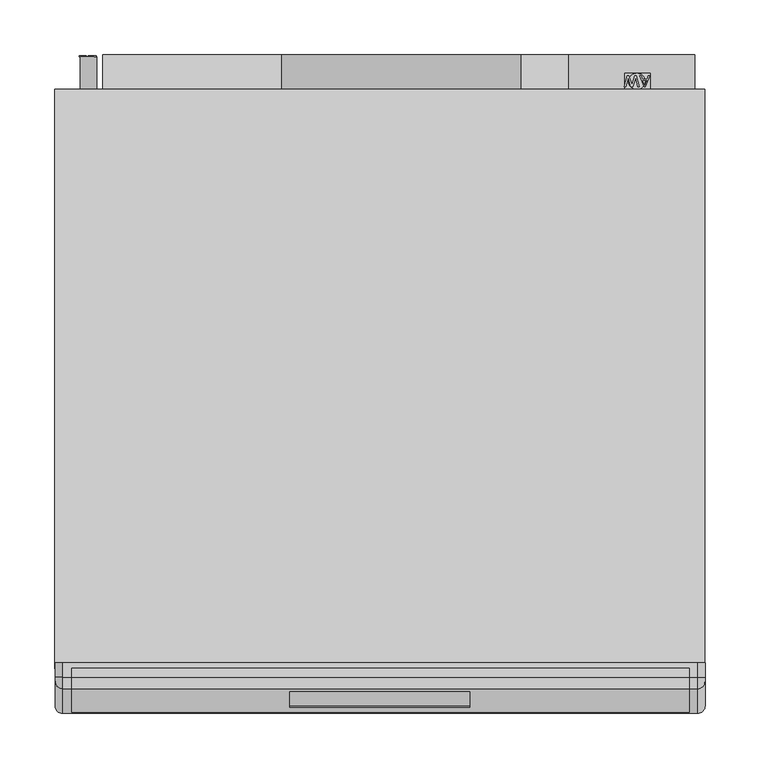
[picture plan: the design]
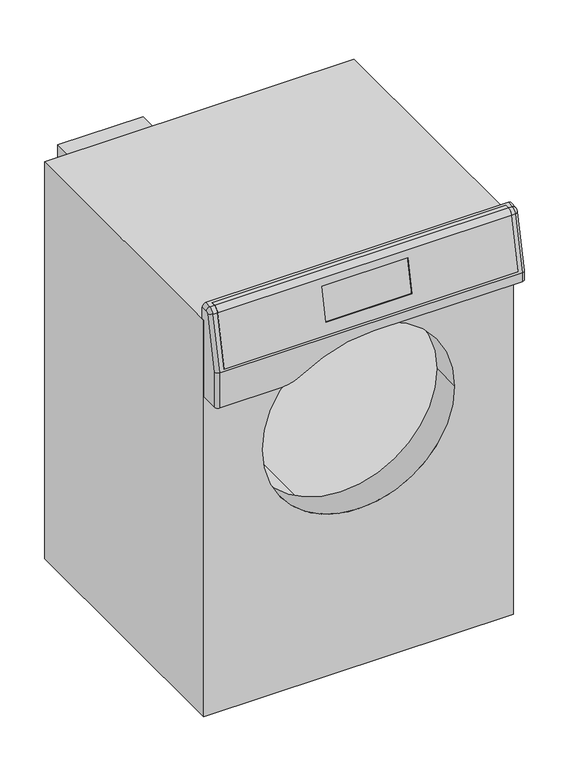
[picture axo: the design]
"""IFC4 building model written with IfcOpenShell, lengths in millimetres: proxy geometry."""

from ifc_helpers import new_model, si_unit, point, frame, frame_2d, origin, origin_with_axes, place, context, project, spatial, polyline, circle_curve, ellipse_curve, trimmed, segment, composite_curve, outline, extrude, source, transform, mapped, element, save
from ifc_brep_helpers import plane_surface, cylinder_surface, revolved_surface, advanced_brep


def specialty_equipment_5b1ebcfc(model_context):
    return source(origin(), model_context, "Body", "SolidModel", [
        advanced_brep(
        [(284.0, -576.5042463, 835.7290958), (284.0, -566.9845398, 843.6465521), (284.0, -558.5, 843.8687276), (284.0, -558.5, 844.8690704), (284.0, -567.0107168, 844.6462094), (284.0, -577.4823939, 835.9370075), (284.0, -599.1497738, 734.0), (284.0, -598.1274332, 734.0), (-282.0, -576.5042463, 835.7290958), (-282.0, -598.1274332, 734.0), (-282.0, -599.1497738, 734.0), (-282.0, -577.4823939, 835.9370075), (-282.0, -567.0107168, 844.6462094), (-282.0, -558.5, 844.8690704), (-282.0, -558.5, 843.8687276), (-282.0, -566.9845398, 843.6465521), (82.5, -580.4447963, 822.0), (82.5, -594.2609728, 757.0), (-82.5, -594.2609728, 757.0), (-82.5, -580.4447963, 822.0), (82.5, -593.2386322, 757.0), (82.5, -579.4224557, 822.0), (-82.5, -579.4224557, 822.0), (-82.5, -593.2386322, 757.0)],
        [
            (0, 1, circle_curve(frame((284.0, -566.7227703, 833.6499789), z_axis=(-1.0, 0.0, 0.0), x_axis=(0.0, 1.0, 0.0)), 10.0)),
            (1, 2),
            (2, 3),
            (3, 4),
            (4, 5, circle_curve(frame((284.0, -566.7227703, 833.6499789), z_axis=(1.0, 0.0, 0.0), x_axis=(0.0, 1.0, 0.0)), 11.0)),
            (5, 6),
            (6, 7),
            (7, 0),
            (8, 9),
            (9, 10),
            (10, 11),
            (11, 12, circle_curve(frame((-282.0, -566.7227703, 833.6499789), z_axis=(-1.0, 0.0, 0.0), x_axis=(0.0, 1.0, 0.0)), 11.0)),
            (12, 13),
            (13, 14),
            (14, 15),
            (15, 8, circle_curve(frame((-282.0, -566.7227703, 833.6499789), z_axis=(1.0, 0.0, 0.0), x_axis=(0.0, 1.0, 0.0)), 10.0)),
            (0, 8),
            (15, 1),
            (14, 2),
            (13, 3),
            (12, 4),
            (11, 5),
            (10, 6),
            (16, 17),
            (17, 18),
            (18, 19),
            (19, 16),
            (9, 7),
            (20, 21),
            (21, 22),
            (22, 23),
            (23, 20),
            (20, 17),
            (16, 21),
            (22, 19),
            (18, 23),
        ],
        [
            plane_surface(frame((284.0, -556.7227703, 833.6499789), z_axis=(1.0, 0.0, 0.0), x_axis=(0.0, 0.0, -1.0))),
            plane_surface(frame((-282.0, -556.7227703, 833.6499789), z_axis=(-1.0, 0.0, 0.0), x_axis=(0.0, 0.0, 1.0))),
            revolved_surface(polyline([(-282.0, -556.7227703, 833.6499789), (284.0, -556.7227703, 833.6499789)]), (-282.0, -566.7227703, 833.6499789), (-1.0, 0.0, 0.0)),
            plane_surface(frame((284.0, -566.9845398, 843.6465521), z_axis=(0.0, 0.026176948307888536, -0.9996573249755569), x_axis=(-1.0, 0.0, 0.0))),
            plane_surface(frame((284.0, -558.5, 843.8687276), z_axis=(0.0, 1.0, 0.0), x_axis=(-1.0, 0.0, 0.0))),
            plane_surface(frame((284.0, -558.5, 844.8690704), z_axis=(0.0, -0.026176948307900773, 0.9996573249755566), x_axis=(-1.0, 0.0, 0.0))),
            cylinder_surface(frame((-282.0, -566.7227703, 833.6499789), z_axis=(1.0, 0.0, 0.0), x_axis=(0.0, 1.0, 0.0)), 11.0),
            plane_surface(frame((284.0, -577.4823939, 835.9370075), z_axis=(0.0, -0.9781476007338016, 0.2079116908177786), x_axis=(-1.0, 0.0, 0.0))),
            plane_surface(frame((284.0, -599.1497738, 734.0), z_axis=(0.0, 0.0, -1.0), x_axis=(-1.0, 0.0, 0.0))),
            plane_surface(frame((284.0, -598.1274332, 734.0), z_axis=(0.0, 0.9781476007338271, -0.20791169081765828), x_axis=(-1.0, 0.0, 0.0))),
            plane_surface(frame((82.5, -580.4447963, 822.0), z_axis=(-1.0, 0.0, 0.0), x_axis=(0.0, -1.0, 0.0))),
            plane_surface(frame((-82.5, -580.4447963, 822.0), z_axis=(1.0, 0.0, 0.0), x_axis=(0.0, 1.0, 0.0))),
            plane_surface(frame((82.5, -579.4224557, 822.0), z_axis=(0.0, 0.0, -1.0), x_axis=(-1.0, 0.0, 0.0))),
            plane_surface(frame((82.5, -594.2609728, 757.0), z_axis=(0.0, 0.0, 1.0), x_axis=(-1.0, 0.0, 0.0))),
        ],
        [
            (0, [[1, 2, 3, 4, 5, 6, 7, 8]]),
            (1, [[9, 10, 11, 12, 13, 14, 15, 16]]),
            (2, [[-1, 17, -16, 18]]),
            (3, [[-2, -18, -15, 19]]),
            (4, [[-3, -19, -14, 20]]),
            (5, [[-4, -20, -13, 21]]),
            (6, [[-5, -21, -12, 22]]),
            (7, [[-6, -22, -11, 23], [24, 25, 26, 27]]),
            (8, [[-7, -23, -10, 28]]),
            (9, [[-8, -28, -9, -17], [29, 30, 31, 32]]),
            (10, [[33, -24, 34, -29]]),
            (11, [[35, -26, 36, -31]]),
            (12, [[-34, -27, -35, -30]]),
            (13, [[-33, -32, -36, -25]]),
        ],
    ),
        advanced_brep(
        [(298.5, -559.0, 815.0), (298.5, -553.5, 815.0), (298.5, -553.5, 837.9976005), (298.5, -566.8274781, 837.6486082), (298.5, -570.6353607, 834.4816256), (298.5, -593.0, 729.2642704), (298.5, -593.0, 712.0), (298.5, -559.0, 712.0), (-297.5, -559.0, 815.0), (-297.5, -559.0, 659.0), (-297.5, -593.0, 659.0), (-297.5, -593.0, 729.2642704), (-297.5, -570.6353607, 834.4816256), (-297.5, -566.8274781, 837.6486082), (-297.5, -553.5, 837.9976005), (-297.5, -553.5, 815.0), (-290.5, -553.5, 845.0), (291.5, -553.5, 845.0), (284.0, -558.5, 844.8690704), (284.0, -567.0107168, 844.6462094), (291.5, -567.0107168, 844.6462094), (-290.5, -567.0107168, 844.6462094), (-282.0, -567.0107168, 844.6462094), (-282.0, -558.5, 844.8690704), (284.0, -577.4823939, 835.9370075), (291.5000072, -577.4823939, 835.9370075), (-282.0, -577.4823939, 835.9370075), (-290.5, -577.4823939, 835.9370075), (284.0, -599.1497738, 734.0), (-282.0, -599.1497738, 734.0), (-290.5, -600.0, 730.0), (291.5, -600.0, 730.0), (-290.5, -600.0, 659.0), (-170.6302935, -600.0, 659.0), (-135.780818, -600.0, 669.5165354), (5.0, -600.0, 712.0), (291.5, -600.0, 712.0), (-170.6302935, -559.0, 659.0), (5.0, -559.0, 712.0), (-135.780818, -559.0, 669.5165354), (284.0, -558.5, 843.8687276), (284.0, -566.9845398, 843.6465521), (284.0, -576.5042463, 835.7290958), (284.0, -598.1274332, 734.0), (-282.0, -598.1274332, 734.0), (-282.0, -576.5042463, 835.7290958), (-282.0, -566.9845398, 843.6465521), (-282.0, -558.5, 843.8687276)],
        [
            (0, 1),
            (1, 2),
            (2, 3),
            (3, 4, circle_curve(frame((298.5, -566.7227703, 833.6499789), z_axis=(1.0, 0.0, 0.0), x_axis=(0.0, -0.02617694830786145, 0.9996573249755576)), 4.0)),
            (4, 5),
            (5, 6),
            (6, 7),
            (7, 0),
            (8, 9),
            (9, 10),
            (10, 11),
            (11, 12),
            (12, 13, circle_curve(frame((-297.5, -566.7227703, 833.6499789), z_axis=(-1.0, 0.0, 0.0), x_axis=(0.0, -0.9781476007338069, 0.20791169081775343)), 4.0)),
            (13, 14),
            (14, 15),
            (15, 8),
            (0, 8),
            (15, 1),
            (14, 16, ellipse_curve(frame((-290.5, -553.5, 837.9976005), z_axis=(0.0, 1.0, 0.0), x_axis=(0.0, 0.0, 1.0)), 7.0023995, 7.0)),
            (16, 17),
            (17, 2, ellipse_curve(frame((291.5, -553.5, 837.9976005), z_axis=(0.0, 1.0, 0.0), x_axis=(0.0, 0.0, -1.0)), 7.0023995, 7.0)),
            (18, 19),
            (19, 20),
            (20, 17),
            (16, 21),
            (21, 22),
            (22, 23),
            (23, 18),
            (19, 24, circle_curve(frame((284.0, -566.7227703, 833.6499789), z_axis=(1.0, 0.0, 0.0), x_axis=(0.0, 1.0, 0.0)), 11.0)),
            (24, 25),
            (25, 20, circle_curve(frame((291.5, -566.7227703, 833.6499789), z_axis=(-1.0, 0.0, 0.0), x_axis=(0.0, 1.0, 0.0)), 11.0)),
            (26, 22, circle_curve(frame((-282.0, -566.7227703, 833.6499789), z_axis=(-1.0, 0.0, 0.0), x_axis=(0.0, 1.0, 0.0)), 11.0)),
            (21, 27, circle_curve(frame((-290.5, -566.7227703, 833.6499789), z_axis=(1.0, 0.0, 0.0), x_axis=(0.0, 1.0, 0.0)), 11.0)),
            (27, 26),
            (24, 28),
            (28, 29),
            (29, 26),
            (27, 30),
            (30, 31),
            (31, 25),
            (30, 32),
            (32, 33),
            (33, 34, circle_curve(frame((-170.6302935, -600.0, 722.0), z_axis=(0.0, -1.0, 0.0), x_axis=(1.0, 0.0, 0.0)), 63.0)),
            (34, 35, circle_curve(frame((5.0, -600.0, 457.5), z_axis=(0.0, 1.0, 0.0), x_axis=(1.0, 0.0, 0.0)), 254.5)),
            (35, 36),
            (36, 31),
            (9, 37),
            (37, 33),
            (32, 10, circle_curve(frame((-290.5, -593.0, 659.0), z_axis=(0.0, 0.0, -1.0), x_axis=(0.0, 1.0, 0.0)), 7.0)),
            (7, 38),
            (38, 39, circle_curve(frame((5.0, -559.0, 457.5), z_axis=(0.0, -1.0, 0.0), x_axis=(1.0, 0.0, 0.0)), 254.5)),
            (39, 37, circle_curve(frame((-170.6302935, -559.0, 722.0), z_axis=(0.0, 1.0, 0.0), x_axis=(1.0, 0.0, 0.0)), 63.0)),
            (18, 40),
            (40, 41),
            (41, 42, circle_curve(frame((284.0, -566.7227703, 833.6499789), z_axis=(1.0, 0.0, 0.0), x_axis=(0.0, 1.0, 0.0)), 10.0)),
            (42, 43),
            (43, 28),
            (29, 44),
            (44, 45),
            (45, 46, circle_curve(frame((-282.0, -566.7227703, 833.6499789), z_axis=(-1.0, 0.0, 0.0), x_axis=(0.0, 1.0, 0.0)), 10.0)),
            (46, 47),
            (47, 23),
            (43, 44),
            (42, 45),
            (41, 46),
            (40, 47),
            (30, 11, ellipse_curve(frame((-290.5, -593.0, 729.2642704), z_axis=(0.0, -0.10452846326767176, -0.9945218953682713), x_axis=(0.0, -0.9945218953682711, 0.10452846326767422)), 7.038558, 7.0)),
            (27, 12, circle_curve(frame((-290.5, -570.6353607, 834.4816256), z_axis=(0.0, -0.20791169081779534, -0.978147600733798), x_axis=(0.0, 0.978147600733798, -0.20791169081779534)), 7.0)),
            (21, 13, circle_curve(frame((-290.5, -566.8274781, 837.6486082), z_axis=(0.0, -0.9996573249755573, -0.026176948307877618), x_axis=(0.0, 0.026176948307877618, -0.9996573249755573)), 7.0)),
            (20, 3, circle_curve(frame((291.5, -566.8274781, 837.6486082), z_axis=(0.0, 0.9996573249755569, 0.026176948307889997), x_axis=(1.0, 0.0, 0.0)), 7.0)),
            (25, 4, circle_curve(frame((291.5, -570.6353607, 834.4816256), z_axis=(0.0, 0.20791169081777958, 0.9781476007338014), x_axis=(1.0, 0.0, 0.0)), 7.0)),
            (31, 5, ellipse_curve(frame((291.5, -593.0, 729.2642704), z_axis=(0.0, 0.10452846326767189, 0.9945218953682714), x_axis=(0.0, -0.9945218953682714, 0.1045284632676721)), 7.038558, 7.0)),
            (36, 6, circle_curve(frame((291.5, -593.0, 712.0), z_axis=(0.0, 0.0, 1.0), x_axis=(1.0, 0.0, 0.0)), 7.0)),
            (35, 38),
            (34, 39),
        ],
        [
            plane_surface(frame((298.5, -553.5, 815.0), z_axis=(1.0, 0.0, 0.0), x_axis=(0.0, 1.0, 0.0))),
            plane_surface(frame((-297.5, -553.5, 815.0), z_axis=(-1.0, 0.0, 0.0), x_axis=(0.0, -1.0, 0.0))),
            plane_surface(frame((298.5, -559.0, 815.0), z_axis=(0.0, 0.0, -1.0), x_axis=(-1.0, 0.0, 0.0))),
            plane_surface(frame((298.5, -553.5, 815.0), z_axis=(0.0, 1.0, 0.0), x_axis=(-1.0, 0.0, 0.0))),
            plane_surface(frame((298.5, -553.5, 845.0), z_axis=(0.0, -0.026176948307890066, 0.9996573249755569), x_axis=(-1.0, 0.0, 0.0))),
            cylinder_surface(frame((-297.5, -566.7227703, 833.6499789), z_axis=(1.0, 0.0, 0.0), x_axis=(0.0, 1.0, 0.0)), 11.0),
            plane_surface(frame((298.5, -577.4823939, 835.9370075), z_axis=(0.0, -0.978147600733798, 0.20791169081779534), x_axis=(-1.0, 0.0, 0.0))),
            plane_surface(frame((298.5, -600.0, 730.0), z_axis=(0.0, -1.0, 0.0), x_axis=(-1.0, 0.0, 0.0))),
            plane_surface(frame((298.5, -600.0, 659.0), z_axis=(0.0, 0.0, -1.0), x_axis=(-1.0, 0.0, 0.0))),
            plane_surface(frame((298.5, -559.0, 659.0), z_axis=(0.0, 1.0, 0.0), x_axis=(-1.0, 0.0, 0.0))),
            plane_surface(frame((284.0, -599.1497738, 734.0), z_axis=(-1.0, 0.0, 0.0), x_axis=(0.0, 1.0, 0.0))),
            plane_surface(frame((-282.0, -599.1497738, 734.0), z_axis=(1.0, 0.0, 0.0), x_axis=(0.0, -1.0, 0.0))),
            plane_surface(frame((284.0, -599.1497738, 734.0), z_axis=(0.0, 0.0, 1.0), x_axis=(-1.0, 0.0, 0.0))),
            plane_surface(frame((284.0, -598.1274332, 734.0), z_axis=(0.0, -0.9781476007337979, 0.20791169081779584), x_axis=(-1.0, 0.0, 0.0))),
            cylinder_surface(frame((-282.0, -566.7227703, 833.6499789), z_axis=(-1.0, 0.0, 0.0), x_axis=(0.0, 1.0, 0.0)), 10.0),
            plane_surface(frame((284.0, -566.9845398, 843.6465521), z_axis=(0.0, -0.026176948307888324, 0.9996573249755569), x_axis=(-1.0, 0.0, 0.0))),
            plane_surface(frame((284.0, -558.5, 843.8687276), z_axis=(0.0, -1.0, 0.0), x_axis=(-1.0, 0.0, 0.0))),
            cylinder_surface(frame((-290.5, -593.0, 659.0), z_axis=(0.0, 0.0, 1.0), x_axis=(0.0, 1.0, 0.0)), 7.0),
            cylinder_surface(frame((-290.5, -593.1529668, 728.5446182), z_axis=(0.0, 0.20791169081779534, 0.978147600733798), x_axis=(0.0, 0.978147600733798, -0.20791169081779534)), 7.0),
            revolved_surface(trimmed(ellipse_curve(frame((-290.5, -570.6353607, 834.4816256), z_axis=(0.0, -0.2079116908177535, -0.9781476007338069), x_axis=(0.0, 0.9781476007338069, -0.2079116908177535)), 7.0, 7.0), [point((-290.5, -577.4823939, 835.9370075))], [point((-297.5, -570.6353607, 834.4816256))], True, "CARTESIAN"), (-297.5, -566.7227703, 833.6499789), (-1.0, 0.0, 0.0)),
            cylinder_surface(frame((-290.5, -566.8274781, 837.6486082), z_axis=(0.0, 0.9996573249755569, 0.02617694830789), x_axis=(0.0, 0.02617694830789, -0.9996573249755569)), 7.0),
            cylinder_surface(frame((291.5, -553.3167614, 838.0023987), z_axis=(0.0, -0.9996573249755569, -0.026176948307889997), x_axis=(1.0, 0.0, 0.0)), 7.0),
            revolved_surface(trimmed(ellipse_curve(frame((291.5, -566.8274781, 837.6486082), z_axis=(0.0, 0.9996573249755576, 0.02617694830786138), x_axis=(1.0, 0.0, 0.0)), 7.0, 7.0), [point((291.5, -567.0107168, 844.6462094))], [point((298.5, -566.8274781, 837.6486082))], True, "CARTESIAN"), (298.5, -566.7227703, 833.6499789), (1.0, 0.0, 0.0)),
            cylinder_surface(frame((291.5, -570.6353607, 834.4816256), z_axis=(0.0, -0.20791169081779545, -0.9781476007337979), x_axis=(1.0, 0.0, 0.0)), 7.0),
            cylinder_surface(frame((291.5, -593.0, 730.0), z_axis=(0.0, 0.0, -1.0), x_axis=(1.0, 0.0, 0.0)), 7.0),
            plane_surface(frame((298.5, -600.0, 712.0), z_axis=(0.0, 0.0, -1.0), x_axis=(0.0, 1.0, 0.0))),
            revolved_surface(polyline([(259.5, -600.0, 457.5), (259.5, -559.0, 457.5)]), (5.0, -559.0, 457.5), (0.0, -1.0, 0.0)),
            cylinder_surface(frame((-170.6302935, -559.0, 722.0), z_axis=(0.0, 1.0, 0.0), x_axis=(1.0, 0.0, 0.0)), 63.0),
        ],
        [
            (0, [[1, 2, 3, 4, 5, 6, 7, 8]]),
            (1, [[9, 10, 11, 12, 13, 14, 15, 16]]),
            (2, [[-1, 17, -16, 18]]),
            (3, [[-18, -15, 19, 20, 21, -2]]),
            (4, [[22, 23, 24, -20, 25, 26, 27, 28]]),
            (5, [[29, 30, 31, -23]]),
            (5, [[32, -26, 33, 34]]),
            (6, [[35, 36, 37, -34, 38, 39, 40, -30]]),
            (7, [[41, 42, 43, 44, 45, 46, -39]]),
            (8, [[-10, 47, 48, -42, 49]]),
            (9, [[-9, -17, -8, 50, 51, 52, -47]]),
            (10, [[53, 54, 55, 56, 57, -35, -29, -22]]),
            (11, [[58, 59, 60, 61, 62, -27, -32, -37]]),
            (12, [[-57, 63, -58, -36]]),
            (13, [[-56, 64, -59, -63]]),
            (14, [[-55, 65, -60, -64]]),
            (15, [[-54, 66, -61, -65]]),
            (16, [[-53, -28, -62, -66]]),
            (17, [[67, -11, -49, -41]]),
            (18, [[-67, -38, 68, -12]]),
            (19, [[-68, -33, 69, -13]]),
            (20, [[-69, -25, -19, -14]]),
            (21, [[70, -3, -21, -24]]),
            (22, [[-70, -31, 71, -4]]),
            (23, [[-71, -40, 72, -5]]),
            (24, [[-72, -46, 73, -6]]),
            (25, [[74, -50, -7, -73, -45]]),
            (26, [[-74, -44, 75, -51]]),
            (27, [[-75, -43, -48, -52]]),
        ],
    ),
        extrude(outline(polyline([(247.0, -259.6227397), (257.045631, -259.6227397), (257.045631, -266.843037), (255.7899271, -266.843037), (255.7899271, -260.8784436), (252.8076304, -260.8784436), (252.8076304, -266.529111), (251.5519266, -266.529111), (251.5519266, -260.8784436), (248.2557039, -260.8784436), (248.2557039, -267.0), (247.0, -267.0), (247.0, -259.6227397)])), frame((0.0, 2.0, 0.0), z_axis=(0.0, 1.0, 0.0), x_axis=(0.0, 0.0, 1.0)), (0.0, 0.0, 1.0), 1.0),
        extrude(outline(polyline([(247.0, -268.8835558), (257.045631, -268.8835558), (257.045631, -270.1392597), (248.2557039, -270.1392597), (248.2557039, -275.1620752), (247.0, -275.1620752), (247.0, -268.8835558)])), frame((0.0, 2.0, 0.0), z_axis=(0.0, 1.0, 0.0), x_axis=(0.0, 0.0, 1.0)), (0.0, 0.0, 1.0), 1.0),
        extrude(outline(polyline([(247.6863847, -15.5), (243.676471, -25.545631), (242.6071606, -25.545631), (238.5972469, -15.5), (239.9240746, -15.5), (241.074319, -18.6392597), (245.2117652, -18.6392597), (246.359557, -15.5), (247.6863847, -15.5)]), holes=[polyline([(244.7506864, -19.8949636), (241.5329452, -19.8949636), (242.4379349, -22.364678), (243.1418158, -24.2899271), (243.7672152, -22.5805021), (244.7506864, -19.8949636)])]), frame((0.0, 0.0, 306.0), z_axis=(0.0, 0.0, 1.0), x_axis=(1.0, 0.0, 0.0)), (0.0, 0.0, 1.0), 1.0),
        extrude(outline(polyline([(235.4579872, -15.5), (238.1974818, -25.545631), (236.9025372, -25.545631), (235.3132869, -18.9433755), (234.8227776, -16.9053092), (234.2979326, -18.707931), (232.3064648, -25.545631), (230.4400768, -25.545631), (228.9930743, -20.5890343), (227.9164063, -16.9053092), (227.4406122, -18.8845144), (225.8366467, -25.545631), (224.5417021, -25.545631), (227.2836493, -15.5), (228.6251923, -15.5), (231.0335931, -23.2500474), (231.369592, -24.3316204), (231.7472841, -23.0293182), (233.9423134, -15.5), (235.4579872, -15.5)])), frame((0.0, 0.0, 306.0), z_axis=(0.0, 0.0, 1.0), x_axis=(1.0, 0.0, 0.0)), (0.0, 0.0, 1.0), 1.0),
        extrude(outline(composite_curve([segment(trimmed(circle_curve(frame_2d((236.0, -20.5)), 7.5), [point((228.5, -20.5))], [point((243.5, -20.5))], False, "CARTESIAN"), True, "CONTINUOUS"), segment(trimmed(circle_curve(frame_2d((236.0, -20.5)), 7.5), [point((243.5, -20.5))], [point((228.5, -20.5))], False, "CARTESIAN"), True, "CONTINUOUS")], self_intersect=False)), frame((0.0, 0.0, 276.0), z_axis=(0.0, 0.0, 1.0), x_axis=(1.0, 0.0, 0.0)), (0.0, 0.0, 1.0), 30.0),
        extrude(outline(composite_curve([segment(trimmed(circle_curve(frame_2d((252.0, -267.0)), 7.5), [point((252.0, -259.5))], [point((252.0, -274.5))], False, "CARTESIAN"), True, "CONTINUOUS"), segment(trimmed(circle_curve(frame_2d((252.0, -267.0)), 7.5), [point((252.0, -274.5))], [point((252.0, -259.5))], False, "CARTESIAN"), True, "CONTINUOUS")], self_intersect=False)), frame((0.0, -28.0, 0.0), z_axis=(0.0, 1.0, 0.0), x_axis=(0.0, 0.0, 1.0)), (0.0, 0.0, 1.0), 30.0),
        advanced_brep(
        [(-185.0, -501.5, 512.0), (-185.0, -559.0, 512.0), (185.0, -559.0, 512.0), (185.0, -501.5, 512.0), (298.0, -28.0, 815.0), (298.0, -28.0, 8.0), (-298.0, -28.0, 8.0), (-298.0, -28.0, 815.0), (298.0, -559.0, 815.0), (-298.0, -559.0, 815.0), (-298.0, -559.0, 8.0), (298.0, -559.0, 8.0), (298.0, -470.0, 649.0), (298.0, -470.0, 719.0), (298.0, -120.0, 719.0), (298.0, -120.0, 649.0), (298.0, -470.0, 552.0), (298.0, -470.0, 622.0), (298.0, -120.0, 622.0), (298.0, -120.0, 552.0), (298.0, -470.0, 205.5), (298.0, -470.0, 275.5), (298.0, -120.0, 275.5), (298.0, -120.0, 205.5), (298.0, -470.0, 108.5), (298.0, -470.0, 178.5), (298.0, -120.0, 178.5), (298.0, -120.0, 108.5), (0.0, -51.0, 227.0), (0.0, -51.0, 797.0), (0.0, -501.5, 227.0), (0.0, -501.5, 797.0), (291.0, -470.0, 719.0), (291.0, -470.0, 649.0), (291.0, -120.0, 649.0), (291.0, -120.0, 719.0), (291.0, -470.0, 622.0), (291.0, -470.0, 552.0), (291.0, -120.0, 552.0), (291.0, -120.0, 622.0), (291.0, -470.0, 275.5), (291.0, -470.0, 205.5), (291.0, -120.0, 205.5), (291.0, -120.0, 275.5), (291.0, -470.0, 178.5), (291.0, -470.0, 108.5), (291.0, -120.0, 108.5), (291.0, -120.0, 178.5)],
        [
            (0, 1),
            (1, 2, circle_curve(frame((0.0, -559.0, 512.0), z_axis=(0.0, -1.0, 0.0), x_axis=(-1.0, 0.0, 0.0)), 185.0)),
            (2, 3),
            (3, 0, circle_curve(frame((0.0, -501.5, 512.0), z_axis=(0.0, 1.0, 0.0), x_axis=(-1.0, 0.0, 0.0)), 185.0)),
            (0, 3, circle_curve(frame((0.0, -501.5, 512.0), z_axis=(0.0, 1.0, 0.0), x_axis=(-1.0, 0.0, 0.0)), 185.0)),
            (2, 1, circle_curve(frame((0.0, -559.0, 512.0), z_axis=(0.0, -1.0, 0.0), x_axis=(-1.0, 0.0, 0.0)), 185.0)),
            (4, 5),
            (5, 6),
            (6, 7),
            (7, 4),
            (8, 9),
            (9, 10),
            (10, 11),
            (11, 8),
            (4, 8),
            (11, 5),
            (12, 13, circle_curve(frame((298.0, -470.0, 684.0), z_axis=(-1.0, 0.0, 0.0), x_axis=(0.0, 1.0, 0.0)), 35.0)),
            (13, 14),
            (14, 15, circle_curve(frame((298.0, -120.0, 684.0), z_axis=(-1.0, 0.0, 0.0), x_axis=(0.0, 1.0, 0.0)), 35.0)),
            (15, 12),
            (16, 17, circle_curve(frame((298.0, -470.0, 587.0), z_axis=(-1.0, 0.0, 0.0), x_axis=(0.0, 1.0, 0.0)), 35.0)),
            (17, 18),
            (18, 19, circle_curve(frame((298.0, -120.0, 587.0), z_axis=(-1.0, 0.0, 0.0), x_axis=(0.0, 1.0, 0.0)), 35.0)),
            (19, 16),
            (20, 21, circle_curve(frame((298.0, -470.0, 240.5), z_axis=(-1.0, 0.0, 0.0), x_axis=(0.0, 1.0, 0.0)), 35.0)),
            (21, 22),
            (22, 23, circle_curve(frame((298.0, -120.0, 240.5), z_axis=(-1.0, 0.0, 0.0), x_axis=(0.0, 1.0, 0.0)), 35.0)),
            (23, 20),
            (24, 25, circle_curve(frame((298.0, -470.0, 143.5), z_axis=(-1.0, 0.0, 0.0), x_axis=(0.0, 1.0, 0.0)), 35.0)),
            (25, 26),
            (26, 27, circle_curve(frame((298.0, -120.0, 143.5), z_axis=(-1.0, 0.0, 0.0), x_axis=(0.0, 1.0, 0.0)), 35.0)),
            (27, 24),
            (10, 6),
            (9, 7),
            (28, 29, circle_curve(frame((0.0, -51.0, 512.0), z_axis=(0.0, -1.0, 0.0), x_axis=(0.0, 0.0, 1.0)), 285.0)),
            (29, 28, circle_curve(frame((0.0, -51.0, 512.0), z_axis=(0.0, -1.0, 0.0), x_axis=(0.0, 0.0, 1.0)), 285.0)),
            (30, 31, circle_curve(frame((0.0, -501.5, 512.0), z_axis=(0.0, 1.0, 0.0), x_axis=(0.0, 0.0, 1.0)), 285.0)),
            (31, 30, circle_curve(frame((0.0, -501.5, 512.0), z_axis=(0.0, 1.0, 0.0), x_axis=(0.0, 0.0, 1.0)), 285.0)),
            (28, 30),
            (31, 29),
            (32, 33, circle_curve(frame((291.0, -470.0, 684.0), z_axis=(1.0, 0.0, 0.0), x_axis=(0.0, 1.0, 0.0)), 35.0)),
            (33, 34),
            (34, 35, circle_curve(frame((291.0, -120.0, 684.0), z_axis=(1.0, 0.0, 0.0), x_axis=(0.0, 1.0, 0.0)), 35.0)),
            (35, 32),
            (36, 37, circle_curve(frame((291.0, -470.0, 587.0), z_axis=(1.0, 0.0, 0.0), x_axis=(0.0, 1.0, 0.0)), 35.0)),
            (37, 38),
            (38, 39, circle_curve(frame((291.0, -120.0, 587.0), z_axis=(1.0, 0.0, 0.0), x_axis=(0.0, 1.0, 0.0)), 35.0)),
            (39, 36),
            (40, 41, circle_curve(frame((291.0, -470.0, 240.5), z_axis=(1.0, 0.0, 0.0), x_axis=(0.0, 1.0, 0.0)), 35.0)),
            (41, 42),
            (42, 43, circle_curve(frame((291.0, -120.0, 240.5), z_axis=(1.0, 0.0, 0.0), x_axis=(0.0, 1.0, 0.0)), 35.0)),
            (43, 40),
            (44, 45, circle_curve(frame((291.0, -470.0, 143.5), z_axis=(1.0, 0.0, 0.0), x_axis=(0.0, 1.0, 0.0)), 35.0)),
            (45, 46),
            (46, 47, circle_curve(frame((291.0, -120.0, 143.5), z_axis=(1.0, 0.0, 0.0), x_axis=(0.0, 1.0, 0.0)), 35.0)),
            (47, 44),
            (32, 13),
            (12, 33),
            (15, 34),
            (14, 35),
            (36, 17),
            (16, 37),
            (19, 38),
            (18, 39),
            (40, 21),
            (20, 41),
            (23, 42),
            (22, 43),
            (44, 25),
            (24, 45),
            (27, 46),
            (26, 47),
        ],
        [
            revolved_surface(polyline([(-185.0, -501.5, 512.0), (-185.0, -559.0, 512.0)]), (0.0, -559.0, 512.0), (0.0, 1.0, 0.0)),
            plane_surface(frame((298.0, -28.0, 815.0), z_axis=(0.0, 1.0, 0.0), x_axis=(0.0, 0.0, -1.0))),
            plane_surface(frame((298.0, -559.0, 815.0), z_axis=(0.0, -1.0, 0.0), x_axis=(0.0, 0.0, 1.0))),
            plane_surface(frame((298.0, -28.0, 815.0), z_axis=(1.0, 0.0, 0.0), x_axis=(0.0, -1.0, 0.0))),
            plane_surface(frame((298.0, -28.0, 8.0), z_axis=(0.0, 0.0, -1.0), x_axis=(0.0, -1.0, 0.0))),
            plane_surface(frame((-298.0, -28.0, 8.0), z_axis=(-1.0, 0.0, 0.0), x_axis=(0.0, -1.0, 0.0))),
            plane_surface(frame((-298.0, -28.0, 815.0), z_axis=(0.0, 0.0, 1.0), x_axis=(0.0, -1.0, 0.0))),
            plane_surface(frame((0.0, -51.0, 797.0), z_axis=(0.0, -1.0, 0.0), x_axis=(1.0, 0.0, 0.0))),
            plane_surface(frame((0.0, -501.5, 797.0), z_axis=(0.0, 1.0, 0.0), x_axis=(-1.0, 0.0, 0.0))),
            revolved_surface(polyline([(0.0, -501.5, 797.0), (0.0, -51.0, 797.0)]), (0.0, -51.0, 512.0), (0.0, -1.0, 0.0)),
            plane_surface(frame((291.0, -435.0, 684.0), z_axis=(1.0, 0.0, 0.0), x_axis=(0.0, 0.0, -1.0))),
            revolved_surface(polyline([(298.0, -435.0, 684.0), (291.0, -435.0, 684.0)]), (291.0, -470.0, 684.0), (1.0, 0.0, 0.0)),
            plane_surface(frame((298.0, -470.0, 649.0), z_axis=(0.0, 0.0, 1.0), x_axis=(-1.0, 0.0, 0.0))),
            revolved_surface(polyline([(298.0, -85.0, 684.0), (291.0, -85.0, 684.0)]), (291.0, -120.0, 684.0), (1.0, 0.0, 0.0)),
            plane_surface(frame((298.0, -120.0, 719.0), z_axis=(0.0, 0.0, -1.0), x_axis=(-1.0, 0.0, 0.0))),
            revolved_surface(polyline([(298.0, -435.0, 587.0), (291.0, -435.0, 587.0)]), (298.0, -470.0, 587.0), (1.0, 0.0, 0.0)),
            plane_surface(frame((298.0, -470.0, 552.0), z_axis=(0.0, 0.0, 1.0), x_axis=(-1.0, 0.0, 0.0))),
            revolved_surface(polyline([(298.0, -85.0, 587.0), (291.0, -85.0, 587.0)]), (298.0, -120.0, 587.0), (1.0, 0.0, 0.0)),
            plane_surface(frame((298.0, -120.0, 622.0), z_axis=(0.0, 0.0, -1.0), x_axis=(-1.0, 0.0, 0.0))),
            revolved_surface(polyline([(298.0, -435.0, 240.5), (291.0, -435.0, 240.5)]), (298.0, -470.0, 240.5), (1.0, 0.0, 0.0)),
            plane_surface(frame((298.0, -470.0, 205.5), z_axis=(0.0, 0.0, 1.0), x_axis=(-1.0, 0.0, 0.0))),
            revolved_surface(polyline([(298.0, -85.0, 240.5), (291.0, -85.0, 240.5)]), (298.0, -120.0, 240.5), (1.0, 0.0, 0.0)),
            plane_surface(frame((298.0, -120.0, 275.5), z_axis=(0.0, 0.0, -1.0), x_axis=(-1.0, 0.0, 0.0))),
            revolved_surface(polyline([(298.0, -435.0, 143.5), (291.0, -435.0, 143.5)]), (298.0, -470.0, 143.5), (1.0, 0.0, 0.0)),
            plane_surface(frame((298.0, -470.0, 108.5), z_axis=(0.0, 0.0, 1.0), x_axis=(-1.0, 0.0, 0.0))),
            revolved_surface(polyline([(298.0, -85.0, 143.5), (291.0, -85.0, 143.5)]), (298.0, -120.0, 143.5), (1.0, 0.0, 0.0)),
            plane_surface(frame((298.0, -120.0, 178.5), z_axis=(0.0, 0.0, -1.0), x_axis=(-1.0, 0.0, 0.0))),
        ],
        [
            (0, [[1, 2, 3, 4]]),
            (0, [[-1, 5, -3, 6]]),
            (1, [[7, 8, 9, 10]]),
            (2, [[11, 12, 13, 14], [-2, -6]]),
            (3, [[-7, 15, -14, 16], [17, 18, 19, 20], [21, 22, 23, 24], [25, 26, 27, 28], [29, 30, 31, 32]]),
            (4, [[-8, -16, -13, 33]]),
            (5, [[-9, -33, -12, 34]]),
            (6, [[-10, -34, -11, -15]]),
            (7, [[35, 36]]),
            (8, [[37, 38], [-4, -5]]),
            (9, [[-35, 39, -38, 40]]),
            (9, [[-36, -40, -37, -39]]),
            (10, [[41, 42, 43, 44]]),
            (10, [[45, 46, 47, 48]]),
            (10, [[49, 50, 51, 52]]),
            (10, [[53, 54, 55, 56]]),
            (11, [[-41, 57, -17, 58]]),
            (12, [[-42, -58, -20, 59]]),
            (13, [[-43, -59, -19, 60]]),
            (14, [[-44, -60, -18, -57]]),
            (15, [[-45, 61, -21, 62]]),
            (16, [[-46, -62, -24, 63]]),
            (17, [[-47, -63, -23, 64]]),
            (18, [[-48, -64, -22, -61]]),
            (19, [[-49, 65, -25, 66]]),
            (20, [[-50, -66, -28, 67]]),
            (21, [[-51, -67, -27, 68]]),
            (22, [[-52, -68, -26, -65]]),
            (23, [[-53, 69, -29, 70]]),
            (24, [[-54, -70, -32, 71]]),
            (25, [[-55, -71, -31, 72]]),
            (26, [[-56, -72, -30, -69]]),
        ],
    ),
        extrude(outline(composite_curve([segment(trimmed(circle_curve(frame_2d((-267.5, -61.0)), 16.0), [point((-251.5, -61.0))], [point((-283.5, -61.0))], False, "CARTESIAN"), True, "CONTINUOUS"), segment(trimmed(circle_curve(frame_2d((-267.5, -61.0)), 16.0), [point((-283.5, -61.0))], [point((-251.5, -61.0))], False, "CARTESIAN"), True, "CONTINUOUS")], self_intersect=False)), origin_with_axes(), (0.0, 0.0, 1.0), 8.0),
        extrude(outline(composite_curve([segment(trimmed(circle_curve(frame_2d((267.5, -61.0)), 16.0), [point((283.5, -61.0))], [point((251.5, -61.0))], False, "CARTESIAN"), True, "CONTINUOUS"), segment(trimmed(circle_curve(frame_2d((267.5, -61.0)), 16.0), [point((251.5, -61.0))], [point((283.5, -61.0))], False, "CARTESIAN"), True, "CONTINUOUS")], self_intersect=False)), origin_with_axes(), (0.0, 0.0, 1.0), 8.0),
        extrude(outline(composite_curve([segment(trimmed(circle_curve(frame_2d((267.5, -531.0)), 16.0), [point((283.5, -531.0))], [point((251.5, -531.0))], False, "CARTESIAN"), True, "CONTINUOUS"), segment(trimmed(circle_curve(frame_2d((267.5, -531.0)), 16.0), [point((251.5, -531.0))], [point((283.5, -531.0))], False, "CARTESIAN"), True, "CONTINUOUS")], self_intersect=False)), origin_with_axes(), (0.0, 0.0, 1.0), 8.0),
        extrude(outline(composite_curve([segment(trimmed(circle_curve(frame_2d((-267.5, -531.0)), 16.0), [point((-251.5, -531.0))], [point((-283.5, -531.0))], False, "CARTESIAN"), True, "CONTINUOUS"), segment(trimmed(circle_curve(frame_2d((-267.5, -531.0)), 16.0), [point((-283.5, -531.0))], [point((-251.5, -531.0))], False, "CARTESIAN"), True, "CONTINUOUS")], self_intersect=False)), origin_with_axes(), (0.0, 0.0, 1.0), 8.0),
        advanced_brep(
        [(-8.0, 4.0, 14.0), (-125.6828173, 4.0, 486.0), (128.0718894, 4.0, 498.0), (106.0, 4.0, 288.0), (173.0, 4.0, 288.0), (289.0, 4.0, 172.0), (289.0, 4.0, 131.0), (203.9473319, 4.0, 14.0), (106.0, -28.0, 288.0), (128.0718894, -28.0, 498.0), (-125.6828173, -28.0, 486.0), (-8.0, -28.0, 14.0), (203.9473319, -28.0, 14.0), (289.0, -28.0, 131.0), (289.0, -28.0, 172.0), (248.0, -28.0, 260.4929376), (248.0, -28.0, 276.0), (225.0, -28.0, 276.0), (225.0, -28.0, 275.6918512), (173.0, -28.0, 288.0), (225.0, -13.0, 275.6918512), (248.0, -13.0, 260.4929376), (225.0, -13.0, 276.0), (248.0, -13.0, 276.0)],
        [
            (0, 1),
            (1, 2, circle_curve(frame((-0.003567, 4.0, 517.3353565), z_axis=(0.0, 1.0, 0.0), x_axis=(-1.0, 0.0, 0.0)), 129.5267484)),
            (2, 3),
            (3, 4),
            (4, 5, circle_curve(frame((173.0, 4.0, 172.0), z_axis=(0.0, 1.0, 0.0), x_axis=(-1.0, 0.0, 0.0)), 116.0)),
            (5, 6),
            (6, 7, circle_curve(frame((166.0, 4.0, 131.0), z_axis=(0.0, 1.0, 0.0), x_axis=(-1.0, 0.0, 0.0)), 123.0)),
            (7, 0),
            (8, 9),
            (9, 10, circle_curve(frame((-0.003567, -28.0, 517.3353565), z_axis=(0.0, -1.0, 0.0), x_axis=(-1.0, 0.0, 0.0)), 129.5267484)),
            (10, 11),
            (11, 12),
            (12, 13, circle_curve(frame((166.0, -28.0, 131.0), z_axis=(0.0, -1.0, 0.0), x_axis=(-1.0, 0.0, 0.0)), 123.0)),
            (13, 14),
            (14, 15, circle_curve(frame((173.0, -28.0, 172.0), z_axis=(0.0, -1.0, 0.0), x_axis=(-1.0, 0.0, 0.0)), 116.0)),
            (15, 16),
            (16, 17),
            (17, 18),
            (18, 19, circle_curve(frame((173.0, -28.0, 172.0), z_axis=(0.0, -1.0, 0.0), x_axis=(-1.0, 0.0, 0.0)), 116.0)),
            (19, 8),
            (13, 6),
            (5, 14),
            (11, 0),
            (7, 12),
            (10, 1),
            (3, 8),
            (19, 4),
            (9, 2),
            (18, 20),
            (20, 21, circle_curve(frame((173.0, -13.0, 172.0), z_axis=(0.0, 1.0, 0.0), x_axis=(-1.0, 0.0, 0.0)), 116.0)),
            (21, 15),
            (22, 23),
            (23, 21),
            (20, 22),
            (22, 17),
            (16, 23),
        ],
        [
            plane_surface(frame((289.0, 4.0, 14.0), z_axis=(0.0, 1.0, 0.0), x_axis=(0.0, 0.0, -1.0))),
            plane_surface(frame((289.0, -28.0, 14.0), z_axis=(0.0, -1.0, 0.0), x_axis=(0.0, 0.0, 1.0))),
            plane_surface(frame((289.0, 4.0, 288.0), z_axis=(1.0, 0.0, 0.0), x_axis=(0.0, -1.0, 0.0))),
            plane_surface(frame((289.0, 4.0, 14.0), z_axis=(0.0, 0.0, -1.0), x_axis=(0.0, -1.0, 0.0))),
            plane_surface(frame((-8.0, 4.0, 14.0), z_axis=(-0.970295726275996, 0.0, -0.2419218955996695), x_axis=(0.0, -1.0, 0.0))),
            plane_surface(frame((106.0, 4.0, 288.0), z_axis=(0.0, 0.0, 1.0), x_axis=(0.0, -1.0, 0.0))),
            cylinder_surface(frame((-0.003567, -28.0, 517.3353565), z_axis=(0.0, 1.0, 0.0), x_axis=(-1.0, 0.0, 0.0)), 129.5267484),
            plane_surface(frame((128.0718894, 4.0, 498.0), z_axis=(0.9945218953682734, 0.0, -0.10452846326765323), x_axis=(0.0, -1.0, 0.0))),
            cylinder_surface(frame((166.0, -28.0, 131.0), z_axis=(0.0, -1.0, 0.0), x_axis=(-1.0, 0.0, 0.0)), 123.0),
            cylinder_surface(frame((173.0, -28.0, 172.0), z_axis=(0.0, -1.0, 0.0), x_axis=(-1.0, 0.0, 0.0)), 116.0),
            plane_surface(frame((248.0, -13.0, 276.0), z_axis=(0.0, 1.0, 0.0), x_axis=(1.0, 0.0, 0.0))),
            plane_surface(frame((225.0, -13.0, 276.0), z_axis=(0.0, 0.0, 1.0), x_axis=(0.0, -1.0, 0.0))),
            plane_surface(frame((248.0, -13.0, 276.0), z_axis=(1.0, 0.0, 0.0), x_axis=(0.0, -1.0, 0.0))),
            plane_surface(frame((225.0, -13.0, 259.1798006), z_axis=(-1.0, 0.0, 0.0), x_axis=(0.0, -1.0, 0.0))),
        ],
        [
            (0, [[1, 2, 3, 4, 5, 6, 7, 8]]),
            (1, [[9, 10, 11, 12, 13, 14, 15, 16, 17, 18, 19, 20]]),
            (2, [[21, -6, 22, -14]]),
            (3, [[23, -8, 24, -12]]),
            (4, [[-1, -23, -11, 25]]),
            (5, [[26, -20, 27, -4]]),
            (6, [[-2, -25, -10, 28]]),
            (7, [[-3, -28, -9, -26]]),
            (8, [[-7, -21, -13, -24]]),
            (9, [[-5, -27, -19, 29, 30, 31, -15, -22]]),
            (10, [[32, 33, -30, 34]]),
            (11, [[-32, 35, -17, 36]]),
            (12, [[-36, -16, -31, -33]]),
            (13, [[-35, -34, -29, -18]]),
        ],
    ),
        extrude(outline(composite_curve([segment(polyline([(226.0, -87.0), (342.0, -122.464759)]), True, "CONTINUOUS"), segment(trimmed(circle_curve(frame_2d((324.1353162, -180.897507)), 61.1026428), [point((342.0, -122.464759))], [point((324.0, -242.0))], False, "CARTESIAN"), True, "CONTINUOUS"), segment(polyline([(324.0, -242.0), (107.0, -242.0)]), True, "CONTINUOUS"), segment(trimmed(circle_curve(frame_2d((107.0, -164.5)), 77.5), [point((107.0, -242.0))], [point((107.0, -87.0))], False, "CARTESIAN"), True, "CONTINUOUS"), segment(polyline([(107.0, -87.0), (226.0, -87.0)]), True, "CONTINUOUS")], self_intersect=False)), frame((0.0, -28.0, 0.0), z_axis=(0.0, 1.0, 0.0), x_axis=(0.0, 0.0, 1.0)), (0.0, 0.0, 1.0), 15.0),
        extrude(outline(composite_curve([segment(polyline([(815.0, -254.0), (686.0, -254.0), (686.0, -183.0)]), True, "CONTINUOUS"), segment(trimmed(circle_curve(frame_2d((791.447606, -193.8075151)), 106.0), [point((686.0, -183.0))], [point((770.0, -90.0))], False, "CARTESIAN"), True, "CONTINUOUS"), segment(polyline([(770.0, -90.0), (815.0, -90.0), (815.0, -254.0)]), True, "CONTINUOUS")], self_intersect=False)), frame((0.0, -28.0, 0.0), z_axis=(0.0, 1.0, 0.0), x_axis=(0.0, 0.0, 1.0)), (0.0, 0.0, 1.0), 32.0),
    ])


if __name__ == "__main__":
    model = new_model("IFC4")
    model_context = context("Model", 3, world=origin())
    ifc_project = project(units=[si_unit("LENGTHUNIT", "METRE", prefix="MILLI")], contexts=[model_context])
    site = spatial("IfcSite", under=ifc_project)
    building = spatial("IfcBuilding", under=site)
    placement = place(None, origin())
    specialty_equipment_shape = specialty_equipment_5b1ebcfc(model_context)
    element("IfcBuildingElementProxy", 1, Name="Specialty Equipment", at=placement, inside=building, context=model_context, shape_type="MappedRepresentation", body=[
        mapped(specialty_equipment_shape, transform((0.0, 0.0, 0.0), x_axis=(1.0, 0.0, 0.0), y_axis=(0.0, 1.0, 0.0), z_axis=(0.0, 0.0, 1.0))),
    ])
    save(model, "model.ifc")
